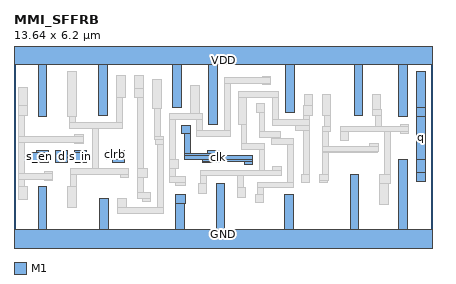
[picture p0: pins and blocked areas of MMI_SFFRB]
MACRO MMI_SFFRB
	CLASS CORE ;
	FOREIGN MMI_SFFRB 0 0 ;
	SIZE 13.64 BY 6.2 ;
	SYMMETRY X Y ;
	SITE CORE1 ;
	PIN d
		DIRECTION input ;
		USE SIGNAL ;
		PORT
			LAYER M1 ;
			RECT 1.36 2.6 1.74 2.98 ;
		END
		AntennaGateArea 0.3465 ;
	END d
	PIN GND
		DIRECTION inout ;
		USE GROUND ;
		PORT
			LAYER M1 ;
			RECT 0.785 0.42 1.065 1.82 ;
			LAYER M1 ;
			RECT 2.8 0.42 3.08 1.435 ;
			LAYER M1 ;
			RECT 5.265 1.265 5.58 1.545 ;
			LAYER M1 ;
			RECT 5.28 0.42 5.56 1.265 ;
			LAYER M1 ;
			RECT 6.6 0.42 6.88 1.91 ;
			LAYER M1 ;
			RECT 8.83 0.42 9.11 1.565 ;
			LAYER M1 ;
			RECT 10.965 0.42 11.245 2.21 ;
			LAYER M1 ;
			RECT 12.555 0.42 12.835 2.685 ;
			LAYER M1 ;
			RECT 0 -0.42 13.645 0.42 ;
		END
	END GND
	PIN q
		DIRECTION output ;
		USE SIGNAL ;
		PORT
			LAYER M1 ;
			RECT 13.145 4.38 13.425 5.58 ;
			LAYER M1 ;
			RECT 13.145 4.11 13.435 4.38 ;
			LAYER M1 ;
			RECT 13.15 2.685 13.435 4.11 ;
			LAYER M1 ;
			RECT 13.145 2.26 13.435 2.685 ;
			LAYER M1 ;
			RECT 13.145 1.985 13.425 2.26 ;
		END
		AntennaDiffArea 0.91245 ;
	END q
	PIN s_en
		DIRECTION input ;
		USE SIGNAL ;
		PORT
			LAYER M1 ;
			RECT 0.74 2.93 1.12 2.98 ;
			LAYER M1 ;
			RECT 0.545 2.65 1.12 2.93 ;
			LAYER M1 ;
			RECT 0.74 2.6 1.12 2.65 ;
		END
		AntennaGateArea 0.51525 ;
	END s_en
	PIN s_in
		DIRECTION input ;
		USE SIGNAL ;
		PORT
			LAYER M1 ;
			RECT 1.98 2.925 2.36 2.98 ;
			LAYER M1 ;
			RECT 1.98 2.645 2.37 2.925 ;
			LAYER M1 ;
			RECT 1.98 2.6 2.36 2.645 ;
		END
		AntennaGateArea 0.17325 ;
	END s_in
	PIN VDD
		DIRECTION inout ;
		USE POWER ;
		PORT
			LAYER M1 ;
			RECT 0 5.78 13.645 6.62 ;
			LAYER M1 ;
			RECT 0.79 4.11 1.07 5.78 ;
			LAYER M1 ;
			RECT 2.76 4.115 3.04 5.78 ;
			LAYER M1 ;
			RECT 5.17 4.395 5.45 5.78 ;
			LAYER M1 ;
			RECT 6.35 3.825 6.63 5.78 ;
			LAYER M1 ;
			RECT 8.875 4.235 9.155 5.78 ;
			LAYER M1 ;
			RECT 11.1 4.115 11.38 5.78 ;
			LAYER M1 ;
			RECT 12.555 4.11 12.835 5.78 ;
		END
	END VDD
	PIN clk
		DIRECTION input ;
		USE CLOCK ;
		PORT
			LAYER M1 ;
			RECT 5.475 3.525 5.755 3.805 ;
			LAYER M1 ;
			RECT 5.555 2.875 5.75 3.525 ;
			LAYER M1 ;
			RECT 6.32 2.875 6.7 2.98 ;
			LAYER M1 ;
			RECT 5.555 2.825 6.7 2.875 ;
			LAYER M1 ;
			RECT 5.555 2.68 7.79 2.825 ;
			LAYER M1 ;
			RECT 6.135 2.63 7.79 2.68 ;
			LAYER M1 ;
			RECT 6.135 2.6 6.7 2.63 ;
			LAYER M1 ;
			RECT 6.135 2.585 6.415 2.6 ;
			LAYER M1 ;
			RECT 7.51 2.545 7.79 2.63 ;
		END
		AntennaGateArea 0.44625 ;
	END clk
	PIN clrb
		DIRECTION input ;
		USE SIGNAL ;
		PORT
			LAYER M1 ;
			RECT 3.02 2.7 3.6 2.98 ;
			LAYER M1 ;
			RECT 3.22 2.6 3.6 2.7 ;
		END
		AntennaGateArea 0.498 ;
	END clrb
	OBS
		LAYER M1 ;
		RECT 0.16 4.455 0.44 5.05 ;
		LAYER M1 ;
		RECT 0.15 4.115 0.44 4.455 ;
		LAYER M1 ;
		RECT 0.15 3.445 0.345 4.115 ;
		LAYER M1 ;
		RECT 1.75 4.11 2.03 5.58 ;
		LAYER M1 ;
		RECT 3.35 4.725 3.63 5.425 ;
		LAYER M1 ;
		RECT 3.94 5.02 4.22 5.425 ;
		LAYER M1 ;
		RECT 3.94 4.725 4.225 5.02 ;
		LAYER M1 ;
		RECT 1.8 3.89 1.995 4.11 ;
		LAYER M1 ;
		RECT 3.35 3.89 3.545 4.725 ;
		LAYER M1 ;
		RECT 1.8 3.7 3.545 3.89 ;
		LAYER M1 ;
		RECT 1.99 3.445 2.27 3.495 ;
		LAYER M1 ;
		RECT 0.15 3.25 2.27 3.445 ;
		LAYER M1 ;
		RECT 0.15 2.25 0.345 3.25 ;
		LAYER M1 ;
		RECT 1.99 3.215 2.27 3.25 ;
		LAYER M1 ;
		RECT 2.575 2.4 2.77 3.7 ;
		LAYER M1 ;
		RECT 4.03 2.4 4.225 4.725 ;
		LAYER M1 ;
		RECT 4.535 4.37 4.815 5.305 ;
		LAYER M1 ;
		RECT 4.6 3.45 4.795 4.37 ;
		LAYER M1 ;
		RECT 5.76 4.195 6.04 5.095 ;
		LAYER M1 ;
		RECT 5.085 4.005 6.15 4.195 ;
		LAYER M1 ;
		RECT 4.6 3.33 4.885 3.45 ;
		LAYER M1 ;
		RECT 4.605 3.17 4.885 3.33 ;
		LAYER M1 ;
		RECT 0.99 2.25 1.27 2.3 ;
		LAYER M1 ;
		RECT 0.15 2.055 1.27 2.25 ;
		LAYER M1 ;
		RECT 0.15 1.825 0.345 2.055 ;
		LAYER M1 ;
		RECT 0.99 2.02 1.27 2.055 ;
		LAYER M1 ;
		RECT 1.85 2.205 3.75 2.4 ;
		LAYER M1 ;
		RECT 0.15 1.39 0.43 1.825 ;
		LAYER M1 ;
		RECT 1.85 1.82 2.04 2.205 ;
		LAYER M1 ;
		RECT 3.47 2.12 3.75 2.205 ;
		LAYER M1 ;
		RECT 4.03 2.12 4.34 2.4 ;
		LAYER M1 ;
		RECT 1.76 1.12 2.04 1.82 ;
		LAYER M1 ;
		RECT 4.03 1.625 4.225 2.12 ;
		LAYER M1 ;
		RECT 4.03 1.61 4.4 1.625 ;
		LAYER M1 ;
		RECT 4.03 1.435 4.465 1.61 ;
		LAYER M1 ;
		RECT 3.39 1.13 3.67 1.435 ;
		LAYER M1 ;
		RECT 4.185 1.33 4.465 1.435 ;
		LAYER M1 ;
		RECT 4.675 1.13 4.865 3.17 ;
		LAYER M1 ;
		RECT 5.085 2.69 5.275 4.005 ;
		LAYER M1 ;
		RECT 5.955 3.625 6.15 4.005 ;
		LAYER M1 ;
		RECT 8.105 5.38 8.385 5.41 ;
		LAYER M1 ;
		RECT 6.88 5.185 8.385 5.38 ;
		LAYER M1 ;
		RECT 6.88 3.625 7.075 5.185 ;
		LAYER M1 ;
		RECT 8.105 5.13 8.385 5.185 ;
		LAYER M1 ;
		RECT 7.32 4.715 8.635 4.91 ;
		LAYER M1 ;
		RECT 7.32 3.85 7.6 4.715 ;
		LAYER M1 ;
		RECT 7.91 4.235 8.19 4.515 ;
		LAYER M1 ;
		RECT 5.955 3.43 7.075 3.625 ;
		LAYER M1 ;
		RECT 7.41 3.215 7.6 3.85 ;
		LAYER M1 ;
		RECT 7.995 3.605 8.185 4.235 ;
		LAYER M1 ;
		RECT 8.445 3.995 8.635 4.715 ;
		LAYER M1 ;
		RECT 9.465 4.445 9.745 4.815 ;
		LAYER M1 ;
		RECT 9.455 4.115 9.745 4.445 ;
		LAYER M1 ;
		RECT 10.055 4.115 10.335 4.815 ;
		LAYER M1 ;
		RECT 11.69 4.32 11.97 4.815 ;
		LAYER M1 ;
		RECT 11.69 4.115 11.98 4.32 ;
		LAYER M1 ;
		RECT 9.455 3.995 9.645 4.115 ;
		LAYER M1 ;
		RECT 8.445 3.805 9.645 3.995 ;
		LAYER M1 ;
		RECT 9.175 3.64 9.645 3.805 ;
		LAYER M1 ;
		RECT 10.14 3.785 10.33 4.115 ;
		LAYER M1 ;
		RECT 11.785 3.785 11.98 4.115 ;
		LAYER M1 ;
		RECT 12.605 3.785 12.885 3.835 ;
		LAYER M1 ;
		RECT 7.995 3.415 8.695 3.605 ;
		LAYER M1 ;
		RECT 8.41 3.365 8.695 3.415 ;
		LAYER M1 ;
		RECT 7.41 3.025 8.19 3.215 ;
		LAYER M1 ;
		RECT 8.41 3.175 9.105 3.365 ;
		LAYER M1 ;
		RECT 8.5 3.17 9.105 3.175 ;
		LAYER M1 ;
		RECT 5.075 2.41 5.355 2.69 ;
		LAYER M1 ;
		RECT 5.085 2.145 5.275 2.41 ;
		LAYER M1 ;
		RECT 8 2.345 8.19 3.025 ;
		LAYER M1 ;
		RECT 8.435 2.345 8.715 2.455 ;
		LAYER M1 ;
		RECT 6.09 2.175 8.715 2.345 ;
		LAYER M1 ;
		RECT 6.09 2.155 8.705 2.175 ;
		LAYER M1 ;
		RECT 5.085 1.955 5.585 2.145 ;
		LAYER M1 ;
		RECT 5.265 1.855 5.58 1.955 ;
		LAYER M1 ;
		RECT 6.09 1.91 6.285 2.155 ;
		LAYER M1 ;
		RECT 6.01 1.595 6.29 1.91 ;
		LAYER M1 ;
		RECT 3.385 0.94 4.865 1.13 ;
		LAYER M1 ;
		RECT 7.3 1.765 7.49 2.155 ;
		LAYER M1 ;
		RECT 8.915 1.955 9.105 3.17 ;
		LAYER M1 ;
		RECT 9.455 2.21 9.645 3.64 ;
		LAYER M1 ;
		RECT 10.055 3.59 10.33 3.785 ;
		LAYER M1 ;
		RECT 10.645 3.59 12.885 3.785 ;
		LAYER M1 ;
		RECT 10.055 3.125 10.25 3.59 ;
		LAYER M1 ;
		RECT 10.645 3.325 10.925 3.59 ;
		LAYER M1 ;
		RECT 11.6 3.125 11.88 3.225 ;
		LAYER M1 ;
		RECT 10.055 2.945 11.88 3.125 ;
		LAYER M1 ;
		RECT 10.055 2.93 11.86 2.945 ;
		LAYER M1 ;
		RECT 10.055 2.21 10.25 2.93 ;
		LAYER M1 ;
		RECT 12.08 2.21 12.27 3.59 ;
		LAYER M1 ;
		RECT 12.605 3.555 12.885 3.59 ;
		LAYER M1 ;
		RECT 7.96 1.765 9.105 1.955 ;
		LAYER M1 ;
		RECT 9.37 1.93 9.65 2.21 ;
		LAYER M1 ;
		RECT 9.96 2.005 10.25 2.21 ;
		LAYER M1 ;
		RECT 9.96 1.93 10.24 2.005 ;
		LAYER M1 ;
		RECT 7.28 1.45 7.56 1.765 ;
		LAYER M1 ;
		RECT 7.96 1.565 8.15 1.765 ;
		LAYER M1 ;
		RECT 7.87 1.285 8.15 1.565 ;
		LAYER M1 ;
		RECT 11.935 1.895 12.27 2.21 ;
		LAYER M1 ;
		RECT 11.935 1.24 12.215 1.895 ;
	END
END MMI_SFFRB
